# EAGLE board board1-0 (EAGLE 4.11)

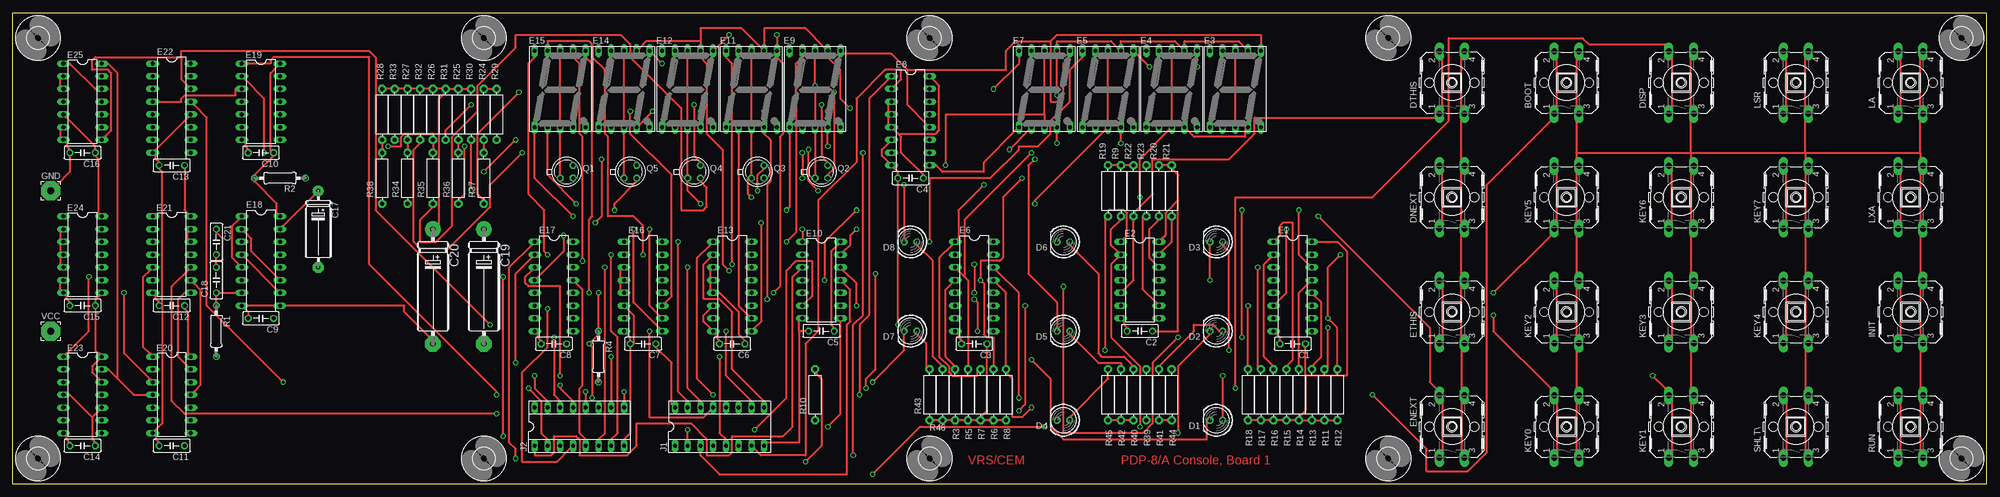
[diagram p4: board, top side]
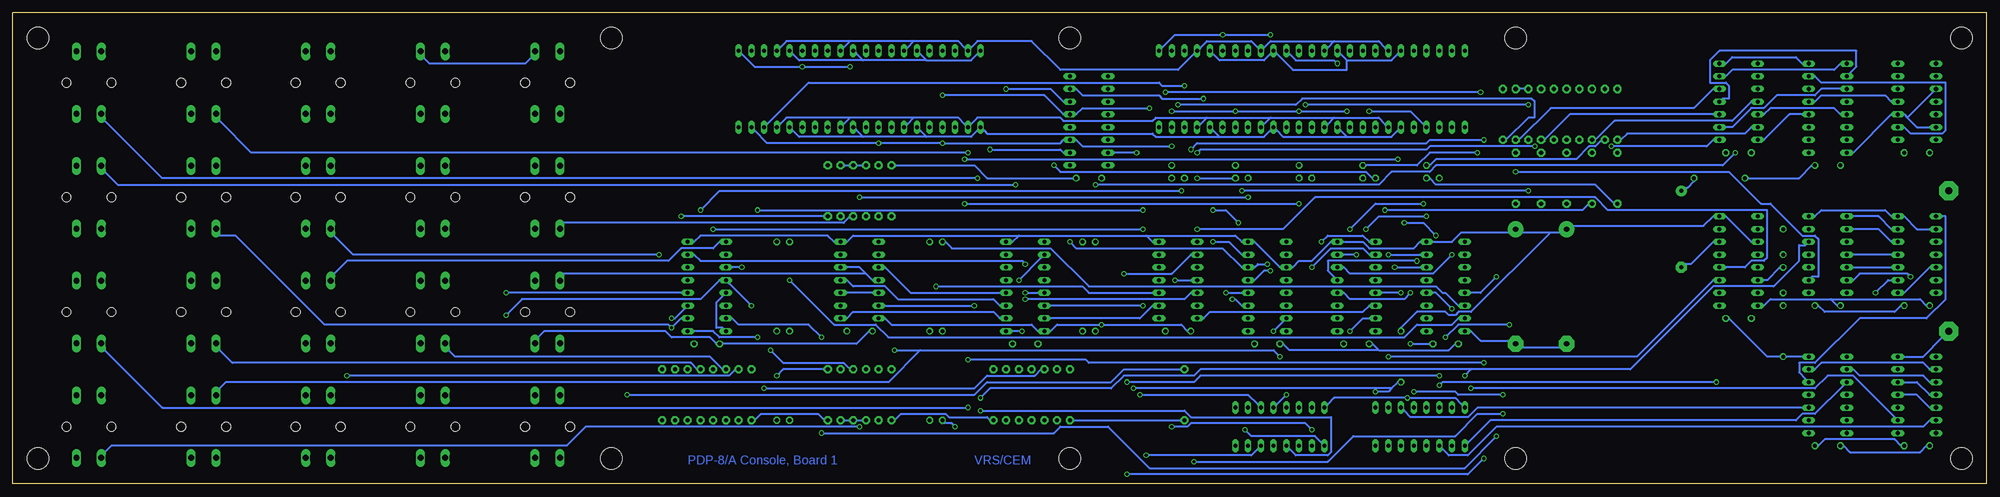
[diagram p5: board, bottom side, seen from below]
Size 393.7 x 93.98 mm. Coordinates in mm from the lower left corner, seen from the top.
Outline: 0,0 0,93.98 393.7,93.98 393.7,0 0,0
Copper layers (1*16): Top 0.035mm / dielectric 1.5mm / Bottom 0.035mm
Design rules "15mils": minimum track width 15mil, minimum drill 24mil, track to track 15mil, track to pad 10mil, pad to pad 10mil, via to via 10mil, smd to smd 10mil, copper to edge 25mil, drill to drill 10mil, minimum pad ring 10mil, minimum via ring 8mil, stop-mask expansion 0mil, vias tented up to drill 0mil, thermal gap 10mil
Net classes: 1 Supply: width 0.381 mm

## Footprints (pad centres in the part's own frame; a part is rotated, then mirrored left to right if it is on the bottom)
B3F-40XX = drill 1.194 long: 1 -6.248,2.489; 2 6.248,2.489; 3 -6.248,-2.489; 4 6.248,-2.489 | hole 1.803: 0,-4.496; 0,4.496
C050-025X075 = drill 0.813 octagon: 1 -2.54,0; 2 2.54,0
E15-5 = drill 0.813 pad 2.159 round: + -7.62,0 | drill 0.813 pad 2.159 octagon: - 7.62,0
E22-6 = drill 1.016 pad 3.15 round: + -11.43,0 | drill 1.016 pad 3.15 octagon: - 11.43,0
LED5MM = drill 0.813 octagon: A -1.27,0; K 1.27,0
DIL16 = drill 0.813 long: 1 -8.89,-3.81; 2 -6.35,-3.81; 3 -3.81,-3.81; 4 -1.27,-3.81; 5 1.27,-3.81; 6 3.81,-3.81; 7 6.35,-3.81; 8 8.89,-3.81; 9 8.89,3.81; 10 6.35,3.81; 11 3.81,3.81; 12 1.27,3.81; 13 -1.27,3.81; 14 -3.81,3.81; 15 -6.35,3.81; 16 -8.89,3.81
DIL14 = drill 0.813 long: 1 -7.62,-3.81; 2 -5.08,-3.81; 3 -2.54,-3.81; 4 0,-3.81; 5 2.54,-3.81; 6 5.08,-3.81; 7 7.62,-3.81; 8 7.62,3.81; 9 5.08,3.81; 10 2.54,3.81; 11 0,3.81; 12 -2.54,3.81; 13 -5.08,3.81; 14 -7.62,3.81
HDSP-M = drill 0.813 long: 1 -5.08,-7.62; 2 -2.54,-7.62; 3 0,-7.62; 4 2.54,-7.62; 5 5.08,-7.62; 6 5.08,7.62; 7 2.54,7.62; 8 0,7.62; 9 -2.54,7.62; 10 -5.08,7.62
3,81/1,4 = drill 1.397 pad 3.81 octagon: 1 0,0
SOCKED-16 = drill 0.813 long: 1 -8.89,-3.81; 2 -6.35,-3.81; 3 -3.81,-3.81; 4 -1.27,-3.81; 5 1.27,-3.81; 6 3.81,-3.81; 7 6.35,-3.81; 8 8.89,-3.81; 9 8.89,3.81; 10 6.35,3.81; 11 3.81,3.81; 12 1.27,3.81; 13 -1.27,3.81; 14 -3.81,3.81; 15 -6.35,3.81; 16 -8.89,3.81
TO18 = drill 0.813 octagon: 1 -1.27,-1.27; 2 1.27,-1.27; 3 1.27,1.27
0207/10 = drill 0.813 octagon: 1 -5.08,0; 2 5.08,0
R-10 = drill 0.813 pad 1.6 octagon: 1 -5.08,0; 2 5.08,0
4,3 = hole 4.3: 0,0

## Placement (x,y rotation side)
BOOT  [B3F-40XX]  309.88,80.01 90 top
C1  0.01  [C050-025X075]  255.27,27.94 180 top
C2  0.01  [C050-025X075]  224.79,30.48 180 top
C3  0.01  [C050-025X075]  191.77,27.94 180 top
C4  0.01  [C050-025X075]  179.07,60.96 180 top
C5  0.01  [C050-025X075]  161.29,30.48 180 top
C6  0.01  [C050-025X075]  143.51,27.94 180 top
C7  0.01  [C050-025X075]  125.73,27.94 180 top
C8  0.01  [C050-025X075]  107.95,27.94 180 top
C9  0.01  [C050-025X075]  49.53,33.02 180 top
C10  0.01  [C050-025X075]  49.53,66.04 180 top
C11  0.01  [C050-025X075]  31.75,7.62 180 top
C12  0.01  [C050-025X075]  31.75,35.56 180 top
C13  0.01  [C050-025X075]  31.75,63.5 180 top
C14  0.01  [C050-025X075]  13.97,7.62 180 top
C15  0.01  [C050-025X075]  13.97,35.56 180 top
C16  0.01  [C050-025X075]  13.97,66.04 180 top
C17  1.0uf  [E15-5]  60.96,50.8 270 top
C18  47pf  [C050-025X075]  40.64,40.64 90 top
C19  6.8uf  [E22-6]  93.98,39.37 270 top
C20  6.8uf  [E22-6]  83.82,39.37 270 top
C21  33pf  [C050-025X075]  40.64,48.26 270 top
D1  MQ  [LED5MM]  240.03,12.7 180 top
D2  SR  [LED5MM]  240.03,30.48 180 top
D3  MD  [LED5MM]  240.03,48.26 180 top
D4  AC  [LED5MM]  209.55,12.7 180 top
D5  STATUS  [LED5MM]  209.55,30.48 180 top
D6  STATE  [LED5MM]  209.55,48.26 180 top
D7  BUS  [LED5MM]  179.07,30.48 180 top
D8  RUN  [LED5MM]  179.07,48.26 180 top
DISP  [B3F-40XX]  332.74,80.01 90 top
DNEXT  [B3F-40XX]  287.02,57.15 90 top
DTHIS  [B3F-40XX]  287.02,80.01 90 top
E1  74LS148N  [DIL16]  255.27,39.37 270 top
E2  74LS08N  [DIL14]  224.79,40.64 270 top
E3  HD-H101  [HDSP-M]  243.84,78.74 0 top
E4  HD-H101  [HDSP-M]  231.14,78.74 0 top
E5  HD-H101  [HDSP-M]  218.44,78.74 0 top
E6  74LS148N  [DIL16]  191.77,39.37 270 top
E7  HD-H101  [HDSP-M]  205.74,78.74 0 top
E8  7446N  [DIL16]  179.07,72.39 270 top
E9  HD-H101  [HDSP-M]  160.02,78.74 0 top
E10  74LS08N  [DIL14]  161.29,40.64 270 top
E11  HD-H101  [HDSP-M]  147.32,78.74 0 top
E12  HD-H101  [HDSP-M]  134.62,78.74 0 top
E13  7446N  [DIL16]  143.51,39.37 270 top
E14  HD-H101  [HDSP-M]  121.92,78.74 0 top
E15  HD-H101  [HDSP-M]  109.22,78.74 0 top
E16  7446N  [DIL16]  125.73,39.37 270 top
E17  74LS145N  [DIL16]  107.95,39.37 270 top
E18  74LS123N  [DIL16]  49.53,44.45 270 top
E19  7416N  [DIL14]  49.53,76.2 270 top
E20  74LS04N  [DIL14]  31.75,17.78 270 top
E21  74LS20N  [DIL14]  31.75,45.72 270 top
E22  74LS42N  [DIL16]  31.75,74.93 270 top
E23  74LS74N  [DIL14]  13.97,17.78 270 top
E24  74LS95N  [DIL14]  13.97,45.72 270 top
E25  74LS90N  [DIL14]  13.97,76.2 270 top
ENEXT  [B3F-40XX]  287.02,11.43 90 top
ETHIS  [B3F-40XX]  287.02,34.29 90 top
GND  [3,81/1,4]  7.62,58.42 0 top
INIT  [B3F-40XX]  378.46,34.29 90 top
J1  [SOCKED-16]  140.97,11.43 0 top
J2  [SOCKED-16]  113.03,11.43 0 top
KEY0  [B3F-40XX]  309.88,11.43 90 top
KEY1  [B3F-40XX]  332.74,11.43 90 top
KEY2  [B3F-40XX]  309.88,34.29 90 top
KEY3  [B3F-40XX]  332.74,34.29 90 top
KEY4  [B3F-40XX]  355.6,34.29 90 top
KEY5  [B3F-40XX]  309.88,57.15 90 top
KEY6  [B3F-40XX]  332.74,57.15 90 top
KEY7  [B3F-40XX]  355.6,57.15 90 top
LA  [B3F-40XX]  378.46,80.01 90 top
LSR  [B3F-40XX]  355.6,80.01 90 top
LXA  [B3F-40XX]  378.46,57.15 90 top
Q1  MPSA05  [TO18]  110.49,62.23 0 top
Q2  MPSA05  [TO18]  161.29,62.23 0 top
Q3  MPSA05  [TO18]  148.59,62.23 0 top
Q4  MPSA05  [TO18]  135.89,62.23 0 top
Q5  MPSA05  [TO18]  123.19,62.23 0 top
R1  10K  [0207/10]  40.64,30.48 270 top
R2  6.8K  [0207/10]  53.34,60.96 0 top
R3  1K  [R-10]  187.96,17.78 90 top
R4  10K  [0207/10]  116.84,25.4 270 top
R5  1K  [R-10]  190.5,17.78 90 top
R6  1K  [R-10]  195.58,17.78 90 top
R7  1K  [R-10]  193.04,17.78 90 top
R8  1K  [R-10]  198.12,17.78 90 top
R9  1K  [R-10]  220.98,58.42 270 top
R10  1K  [R-10]  160.02,17.78 90 top
R11  1K  [R-10]  261.62,17.78 90 top
R12  1K  [R-10]  264.16,17.78 90 top
R13  1K  [R-10]  259.08,17.78 90 top
R14  1K  [R-10]  256.54,17.78 90 top
R15  1K  [R-10]  254,17.78 90 top
R16  1K  [R-10]  251.46,17.78 90 top
R17  1K  [R-10]  248.92,17.78 90 top
R18  1K  [R-10]  246.38,17.78 90 top
R19  1K  [R-10]  218.44,58.42 270 top
R20  1K  [R-10]  228.6,58.42 270 top
R21  1K  [R-10]  231.14,58.42 270 top
R22  1K  [R-10]  223.52,58.42 270 top
R23  1K  [R-10]  226.06,58.42 270 top
R24  470  [R-10]  93.98,73.66 270 top
R25  470  [R-10]  88.9,73.66 270 top
R26  470  [R-10]  83.82,73.66 270 top
R27  470  [R-10]  78.74,73.66 270 top
R28  470  [R-10]  73.66,73.66 270 top
R29  10  [R-10]  96.52,73.66 270 top
R30  10  [R-10]  91.44,73.66 270 top
R31  10  [R-10]  86.36,73.66 270 top
R32  10  [R-10]  81.28,73.66 270 top
R33  27  [R-10]  76.2,73.66 270 top
R34  27  [R-10]  78.74,60.96 90 top
R35  27  [R-10]  83.82,60.96 90 top
R36  27  [R-10]  88.9,60.96 90 top
R37  27  [R-10]  93.98,60.96 90 top
R38  27  [R-10]  73.66,60.96 90 top
R39  330  [R-10]  226.06,17.78 90 top
R40  330  [R-10]  223.52,17.78 90 top
R41  330  [R-10]  228.6,17.78 90 top
R42  330  [R-10]  220.98,17.78 90 top
R43  330  [R-10]  182.88,17.78 90 top
R44  330  [R-10]  231.14,17.78 90 top
R45  330  [R-10]  218.44,17.78 90 top
R46  330  [R-10]  185.42,17.78 90 top
RUN  [B3F-40XX]  378.46,11.43 90 top
SHLT\  [B3F-40XX]  355.6,11.43 90 top
U$2  [4,3]  5.08,5.08 0 top
U$11  [4,3]  93.98,5.08 0 top
U$12  [4,3]  5.08,88.9 0 top
U$13  [4,3]  182.88,5.08 0 top
U$14  [4,3]  274.32,5.08 0 top
U$15  [4,3]  388.62,5.08 0 top
U$16  [4,3]  388.62,88.9 0 top
U$17  [4,3]  274.32,88.9 0 top
U$18  [4,3]  182.88,88.9 0 top
U$19  [4,3]  93.98,88.9 0 top
VCC  [3,81/1,4]  7.62,30.48 0 top

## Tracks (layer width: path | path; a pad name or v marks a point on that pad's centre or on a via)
A  (via drill 0.61)
  Top 0.381: v208.28,77.47 208.28,85.09 E7.7 208.28,87.63 208.28,88.27 219.07,88.27 220.34,87 E5.7 220.98,87.63 220.98,88.27 231.78,88.27 233.04,87 E4.7 233.68,87.63 233.68,88.27 244.47,88.27 245.75,87 E3.7 | v142.88,42.55 141.6,43.81 141.6,66.67 138.43,69.85 138.43,83.82 137.16,85.09 E12.7 137.16,87.63 137.16,88.27 | 137.16,88.27 126.36,88.27 125.09,87 E14.7 | 137.16,88.27 137.16,90.81 145.41,90.81 149.22,87 E11.7 149.86,87.63 149.86,90.81 158.12,90.81 161.93,87 E9.7 162.56,85.09 165.1,82.55 165.1,76.83 v167,74.93
  Bottom 0.381: v208.28,77.47 187.96,77.47 184.15,73.66 E8.13 181.61,73.66 180.34,74.93 v167,74.93 | v142.88,42.55 144.15,42.55 146.05,40.64 E13.13
ADDR0  (via drill 0.61)
  Top 0.381: v142.24,30.48 142.24,21.59 147.32,16.51 J1.10
  Bottom 0.381: v142.24,30.48 140.34,32.38 E13.7
ADDR1  (via drill 0.61)
  Top 0.381: v139.7,17.78 136.53,20.95 136.53,45.09 139.06,47.62 E13.1
  Bottom 0.381: v139.7,17.78 141.6,15.88 J1.12
ADDR2
  Top 0.381: J1.9 149.86,16.51 143.51,22.86 143.51,34.29 140.97,36.83 137.79,36.83 137.79,43.81 139.06,45.09 E13.2
B  (via drill 0.61)
  Top 0.381: v151.76,38.1 153.03,39.37 153.03,69.22 153.67,69.85 153.67,83.82 152.4,85.09 E11.6 152.4,87.63 v152.4,89.53 | v129.54,83.82 127.64,85.72 E14.6 | v142.88,89.53 140.34,87 E12.6 | 178.44,82.55 178.44,75.56 182.25,71.75 E8.12 | 178.44,82.55 175.26,85.72 165.74,85.72 E9.6 | 207.01,88.27 207.01,76.2 208.91,76.2 209.55,76.83 209.55,83.82 210.82,85.09 E7.6 | 207.01,88.27 208.28,89.53 248.92,89.53 248.92,87.63 E3.6 | v226.69,83.19 224.16,85.72 E5.6 | v236.22,83.19 236.22,85.09 E4.6 | 178.44,82.55 198.12,82.55 198.12,86.36 200.03,88.27 207.01,88.27
  Bottom 0.381: v151.76,38.1 148.59,38.1 E13.12 | v129.54,83.82 130.18,84.45 137.79,84.45 139.06,85.72 E12.6 | v142.88,89.53 v152.4,89.53 161.93,89.53 164.47,87 E9.6 | v226.69,83.19 v236.22,83.19 245.75,83.19 248.28,85.72 E3.6
BEMA0  (via drill 0.61)
  Top 0.381: v127,30.48 127,13.34 137.79,13.34 139.06,14.61 J1.13
  Bottom 0.381: v127,30.48 124.46,33.02 123.19,33.02 E16.7
BEMA1  (via drill 0.61)
  Top 0.381: v132.72,48.26 132.72,18.41 134.62,16.51 J1.15
  Bottom 0.381: v132.72,48.26 131.44,49.53 124.46,49.53 123.19,48.26 E16.1
BEMA2  (via drill 0.61)
  Top 0.381: v134.62,43.18 134.62,19.05 137.16,16.51 J1.14
  Bottom 0.381: v134.62,43.18 130.81,46.99 124.46,46.99 123.19,45.72 E16.2
BOOT  (via drill 0.61)
  Top 0.381: BOOT.2 307.98,85.09 307.98,74.93 BOOT.1 306.7,72.39 294,59.69 294,6.35 290.19,2.54 281.94,2.54 281.94,6.99 v271.14,17.78 | v96.52,13.97 34.29,13.97 31.75,16.51 31.75,39.37 34.92,42.55 E21.10 | v158.12,4.45 161.29,7.62 161.29,20.95 160.02,22.23 R10.2
  Bottom 0.381: v271.14,17.78 201.93,17.78 199.39,20.32 174.62,20.32 172.09,22.86 160.66,22.86 R10.2 | v96.52,13.97 101.6,13.97 106.05,9.53 126.36,9.53 131.44,4.45 v158.12,4.45
BPWR-OK  (via drill 0.61)
  Top 0.381: E18.11 52.7,41.27 47.62,46.35 47.62,48.9 46.35,50.16 E18.2 | v119.38,25.4 119.38,16.51 J2.10
  Bottom 0.381: v119.38,25.4 69.85,25.4 54.61,40.64 E18.11
BRUN  (via drill 0.61)
  Top 0.381: v96.52,17.78 96.52,18.41 71.12,43.81 71.12,85.09 52.07,85.09 51.44,84.45 51.44,83.82 46.99,83.82 E19.1 | v114.3,18.41 114.3,16.51 J2.12
  Bottom 0.381: v96.52,17.78 105.41,17.78 106.05,18.41 v114.3,18.41
C  (via drill 0.61)
  Top 0.381: v208.28,67.94 208.28,69.85 E7.4 | v220.98,67.94 220.98,69.85 E5.4 | E4.4 234.31,70.48 235.59,69.22 245.75,69.22 245.75,70.48 E3.4 | v150.5,36.83 150.5,59.69 151.13,60.33 151.13,68.58 149.86,69.85 E11.4 149.86,72.39 v149.86,74.3 | v127.64,74.3 125.09,71.75 E14.4 | v137.16,74.3 137.16,72.39 E12.4 | v162.56,74.3 162.56,72.39 E9.4 162.56,69.85 v162.56,67.31
  Bottom 0.381: E3.4 245.75,70.48 243.21,67.94 v220.98,67.94 v208.28,67.94 184.78,67.94 184.15,68.58 E8.11 181.61,68.58 180.34,67.31 v162.56,67.31 | v150.5,36.83 149.86,36.83 148.59,35.56 E13.11 | v127.64,74.3 v137.16,74.3 v149.86,74.3 v162.56,74.3
D  (via drill 0.61)
  Top 0.381: v198.75,66.67 202.56,70.48 E7.2 | E13.10 146.69,33.66 144.78,35.56 144.78,69.85 E11.2
  Bottom 0.381: v198.75,66.67 184.78,66.67 184.15,66.04 E8.10 | 214,73.03 215.26,71.75 E5.2 | 214,73.03 205.1,73.03 203.84,71.75 E7.2 202.56,71.75 201.29,73.03 184.78,73.03 184.15,72.39 166.37,72.39 165.74,73.03 155.57,73.03 | 226.69,73.03 227.97,71.75 E4.2 | 214,73.03 226.69,73.03 | 226.69,73.03 239.4,73.03 240.66,71.75 E3.2 | 130.18,73.03 121.28,73.03 120.02,71.75 E14.2 | 130.18,73.03 131.44,71.75 E12.2 | 142.88,73.03 144.15,71.75 E11.2 | 142.88,73.03 130.18,73.03 | 155.57,73.03 156.84,71.75 E9.2 | 155.57,73.03 142.88,73.03
DISP  (via drill 0.61)
  Top 0.381: DISP.1 330.83,74.93 330.83,85.09 DISP.2 329.56,87.63 314.32,87.63 313.06,88.9 286.38,88.9 286.38,72.39 271.14,57.15 243.84,57.15 v243.84,19.05 | E6.4 187.32,40.01 186.06,38.73 186.06,25.4 187.96,23.5 R3.2
  Bottom 0.381: v243.84,19.05 201.93,19.05 199.39,21.59 189.87,21.59 188.59,22.86 R3.2
DISP0
  Top 0.381: E17.13 112.39,40.01 113.67,38.73 113.67,19.68 113.03,19.05 113.03,10.16 114.3,8.89 J2.5
DISP1  (via drill 0.61)
  Top 0.381: v118.11,43.18 118.11,10.16 116.84,8.89 J2.6
  Bottom 0.381: v118.11,43.18 113.03,43.18 E17.14
DISP2  (via drill 0.61)
  Top 0.381: v119.38,45.72 119.38,30.48 120.65,29.21 120.65,10.16 119.38,8.89 J2.7
  Bottom 0.381: v119.38,45.72 113.03,45.72 E17.15
DISPINH  (via drill 0.61)
  Top 0.381: v106.68,34.92 106.68,27.3 101.6,22.23 101.6,4.45 108.58,4.45 111.12,6.99 J2.4
  Bottom 0.381: v106.68,34.92 109.86,38.1 110.49,38.1 E17.12
DISPLAY0  (via drill 0.61)
  Top 0.381: v167.64,5.71 167.64,31.75 169.54,33.66 v169.54,66.04
  Bottom 0.381: v167.64,5.71 146.69,5.71 145.41,6.99 J1.6 | v169.54,66.04 173.99,66.04 E8.7
DISPLAY1  (via drill 0.61)
  Top 0.381: v168.91,17.78 168.91,31.75 170.81,33.66 170.81,76.83 174.62,80.64 E8.1
  Bottom 0.381: v168.91,17.78 147.32,17.78 145.41,15.88 J1.11
DISPLAY2
  Top 0.381: J1.7 147.96,6.99 149.22,5.71 158.12,5.71 158.12,27.94 160.66,30.48 160.66,56.52 168.28,64.14 168.28,76.83 173.99,82.55 177.16,82.55 177.16,80.64 175.9,79.38 E8.2
DNEXT
  Top 0.381: DNEXT.1 285.12,52.07 285.12,62.23 DNEXT.2 | E2.9 227.97,36.2 225.43,38.73 225.43,53.34 R23.2
  Bottom 0.381: DNEXT.1 283.85,52.07 227.97,52.07 226.69,53.34 R23.2
DTHIS
  Top 0.381: DTHIS.2 285.12,85.09 285.12,74.93 DTHIS.1 283.85,73.03 247.65,73.03 247.65,69.85 242.57,64.77 227.33,64.77 227.33,57.78 223.52,53.98 R22.2 223.52,52.7 223.52,40.64 221.62,38.73 E2.5
  Bottom 0.381: E2.5 222.25,38.1 227.33,38.1 E2.10
E  (via drill 0.61)
  Top 0.381: E8.9 184.15,63.5 185.42,62.23 193.68,62.23 193.68,64.14 200.03,70.48 E7.1 | v149.22,52.07 149.22,32.38 147.96,31.11 E13.9 | v154.31,54.61 154.94,55.24 154.94,69.85 E9.1
  Bottom 0.381: 211.46,69.22 212.72,70.48 E5.1 | 211.46,69.22 202.56,69.22 201.29,70.48 E7.1 200.03,70.48 199.39,69.85 166.37,69.85 165.74,69.22 153.03,69.22 | 224.16,69.22 225.43,70.48 E4.1 | 211.46,69.22 224.16,69.22 | 224.16,69.22 236.85,69.22 238.12,70.48 E3.1 | 127.64,69.22 118.75,69.22 117.47,70.48 E14.1 | 127.64,69.22 128.91,70.48 E12.1 | 127.64,69.22 140.34,69.22 141.6,70.48 E11.1 142.88,70.48 144.15,69.22 153.03,69.22 | v149.22,52.07 151.76,54.61 v154.31,54.61 | 153.03,69.22 154.31,70.48 E9.1
ENEXT  (via drill 0.61)
  Top 0.381: E2.13 229.24,46.35 231.14,48.26 231.14,52.7 R21.2 | ENEXT.1 285.12,6.35 285.12,16.51 ENEXT.2 283.85,19.05 282.57,20.32 282.57,31.11 v260.35,53.34
  Bottom 0.381: v260.35,53.34 231.78,53.34 R21.2
ETHIS
  Top 0.381: ETHIS.1 285.12,29.21 285.12,39.37 ETHIS.2 | E2.12 227.97,43.81 226.69,45.09 226.69,50.8 228.6,52.7 R20.2
  Bottom 0.381: 223.52,41.91 224.79,43.18 227.33,43.18 E2.12 | 223.52,41.91 222.25,40.64 E2.4 | 223.52,41.91 283.85,41.91 ETHIS.2
EXTPUL\  (via drill 0.61)
  Top 0.381: v121.92,18.41 121.92,16.51 J2.9 | v172.09,41.91 172.09,22.86 170.18,20.95 v170.18,19.05
  Bottom 0.381: 118.75,19.05 119.38,18.41 v121.92,18.41 | 118.75,19.05 117.47,20.32 R4.2 | v172.09,41.91 162.56,41.91 158.75,45.72 E10.2 | 118.75,19.05 v170.18,19.05
F  (via drill 0.61)
  Top 0.381: v154.31,48.26 156.21,50.16 v156.21,76.83 156.21,83.82 157.48,85.09 E9.9
  Bottom 0.381: 214,88.27 215.26,87 E5.9 | 214,88.27 205.1,88.27 203.84,87 E7.9 202.56,87 201.29,88.27 190.5,88.27 184.78,82.55 161.29,82.55 158.12,85.72 E9.9 156.84,87 155.57,88.27 146.69,88.27 145.41,87 E11.9 144.15,87 142.88,88.27 130.18,88.27 | 226.69,88.27 227.97,87 E4.9 | 214,88.27 226.69,88.27 | 226.69,88.27 239.4,88.27 240.66,87 E3.9 | 130.18,88.27 121.28,88.27 120.02,87 E14.9 | 130.18,88.27 131.44,87 E12.9 | v154.31,48.26 151.13,48.26 148.59,45.72 E13.15 | v156.21,76.83 164.47,76.83 165.1,77.47 180.34,77.47 181.61,78.74 E8.15
FUN\  (via drill 0.61)
  Top 0.381: E21.13 34.92,50.16 34.92,48.9 E21.12 | v104.14,21.59 104.14,19.05 106.68,16.51 J2.15 | v200.66,17.14 200.66,38.1 196.22,42.55 E6.14
  Bottom 0.381: 102.87,22.86 v104.14,21.59 | 102.87,22.86 71.12,22.86 54.61,39.37 42.55,39.37 37.47,44.45 37.47,47.62 36.2,47.62 E21.12 | v200.66,17.14 198.75,19.05 174.62,19.05 172.09,21.59 158.12,21.59 156.84,22.86 102.87,22.86
G  (via drill 0.61)
  Top 0.381: v195.58,78.74 200.66,83.82 200.66,85.09 E7.10 | v143.51,43.81 143.51,83.82 142.24,85.09 E11.10 | v182.88,48.26 182.88,60.96 194.94,60.96 200.66,66.67 200.66,67.31 204.47,67.31 207.01,69.85 207.01,72.39 210.82,76.2 210.82,82.55 213.36,85.09 E5.10
  Bottom 0.381: v195.58,78.74 186.69,78.74 184.15,76.2 E8.14 | 211.46,84.45 212.72,85.72 E5.10 | 211.46,84.45 202.56,84.45 201.29,85.72 E7.10 | 224.16,84.45 225.43,85.72 E4.10 | 211.46,84.45 224.16,84.45 | 224.16,84.45 236.85,84.45 238.12,85.72 E3.10 | 127.64,84.45 118.75,84.45 117.47,85.72 E14.10 | 127.64,84.45 128.91,85.72 E12.10 | E9.10 154.31,85.72 153.03,84.45 144.15,84.45 142.88,85.72 E11.10 141.6,85.72 138.43,82.55 127.64,82.55 127.64,84.45 | v143.51,43.81 145.41,43.81 146.05,43.18 E13.14 148.59,43.18 152.4,46.99 181.61,46.99 v182.88,48.26
GND  (via drill 0.61)
  Top 0.381: 380.37,66.04 380.37,72.39 LA.3 380.37,74.93 380.37,85.09 LA.4 | 380.37,66.04 380.37,64.77 LXA.4 380.37,62.23 380.37,52.07 LXA.3 380.37,49.53 380.37,41.91 INIT.4 380.37,39.37 380.37,29.21 INIT.3 380.37,26.67 380.37,19.05 RUN.4 380.37,16.51 380.37,6.35 RUN.3 | 357.5,66.04 357.5,72.39 LSR.3 357.5,74.93 357.5,85.09 LSR.4 | 357.5,66.04 357.5,64.77 KEY7.4 357.5,62.23 357.5,52.07 KEY7.3 357.5,49.53 357.5,41.91 KEY4.4 357.5,39.37 357.5,29.21 KEY4.3 357.5,26.67 357.5,19.05 SHLT\.4 357.5,16.51 357.5,6.35 SHLT\.3 | 334.64,66.04 334.64,72.39 DISP.3 334.64,74.93 334.64,85.09 DISP.4 | 334.64,66.04 334.64,64.77 KEY6.4 334.64,62.23 334.64,52.07 KEY6.3 334.64,49.53 334.64,41.91 KEY3.4 334.64,39.37 334.64,29.21 KEY3.3 334.64,26.67 334.64,19.05 KEY1.4 334.64,16.51 334.64,6.35 KEY1.3 | DTHIS.4 288.93,85.09 288.93,74.93 DTHIS.3 288.93,72.39 288.93,64.77 DNEXT.4 288.93,62.23 288.93,52.07 DNEXT.3 288.93,49.53 288.93,41.91 ETHIS.4 288.93,39.37 288.93,29.21 ETHIS.3 288.93,26.67 288.93,19.05 ENEXT.4 288.93,16.51 288.93,6.35 ENEXT.3 | 311.79,66.04 311.79,72.39 BOOT.3 311.79,74.93 311.79,85.09 BOOT.4 | 311.79,66.04 311.79,64.77 KEY5.4 311.79,62.23 311.79,52.07 KEY5.3 311.79,49.53 311.79,41.91 KEY2.4 311.79,39.37 311.79,29.21 KEY2.3 311.79,26.67 311.79,19.05 KEY0.4 311.79,16.51 311.79,6.35 KEY0.3 | 311.79,66.04 334.64,66.04 | 334.64,66.04 357.5,66.04 | 357.5,66.04 380.37,66.04 | E25.3 9.53,79.38 9.53,80.64 E25.2 | E25.6 9.53,70.48 9.53,69.22 E25.7 10.79,67.94 10.79,67.31 11.43,66.67 C16.2 11.43,65.41 11.43,62.23 8.89,59.69 GND.1 | C10.2 46.99,66.67 46.35,67.31 46.35,67.94 E19.7
  Top 0.381: E22.12 34.92,73.03 28.57,66.67 E22.8 28.57,65.41 28.57,64.77 29.21,64.14 C13.2 29.21,62.87 29.84,62.23 29.84,35.56 | C14.2 11.43,8.26 10.79,8.89 10.79,9.53 E23.7 | C11.2 29.21,8.26 28.57,8.89 28.57,9.53 E20.7 28.57,10.79 29.84,12.06 29.84,35.56 | C15.2 11.43,36.2 10.79,36.83 10.79,37.47 E24.7 9.53,38.73 9.53,40.01 E24.6 | C12.2 29.21,36.2 28.57,36.83 28.57,37.47 E21.7 | C9.2 46.99,33.66 46.99,34.29 46.35,34.92 E18.8 46.99,35.56 52.07,35.56 E18.9 54.61,35.56 78.11,35.56 78.11,34.29 83.19,29.21 C20.- | C12.2 29.84,35.56 | C12.2 29.84,35.56 | C2.2 222.25,31.11 221.62,31.75 221.62,32.38 E2.7 | E1.8 252.09,29.84 252.73,29.21 252.73,28.57 C1.2 | C8.2 105.41,28.57 104.78,29.21 104.78,29.84 E17.8 | J2.8 121.92,8.89 123.19,10.16 123.19,27.3 C7.2 | E16.8 122.56,29.84 123.19,29.21 123.19,28.57 C7.2 | E16.6 122.56,34.92 123.83,33.66 123.83,27.94 C7.2 | E8.6 174.62,67.94 173.35,66.67 173.35,65.41 174.62,64.14 E8.8 175.9,62.87 176.53,62.23 176.53,61.59 C4.2 176.53,60.33 v176.53,31.75 | C6.2 140.97,28.57 140.34,29.21 140.34,29.84 E13.8 139.06,31.11 137.79,32.38 137.79,33.66 139.06,34.92 E13.6 | C3.2 189.23,28.57 188.59,29.21 188.59,29.84 E6.8 | 156.84,30.48 156.84,32.38 E10.7 | 156.84,30.48 156.84,8.26 150.5,8.26 J1.8 | 156.84,30.48 158.12,30.48 C5.2
  Bottom 0.381: DTHIS.4 290.19,85.09 291.46,83.82 310.51,83.82 311.79,85.09 BOOT.4 | 15.88,73.03 13.97,71.12 11.43,71.12 E25.6 | 15.88,73.03 16.51,73.66 E25.10 19.05,73.66 26.67,66.04 E22.8 | 15.88,73.03 10.79,78.11 E25.3 | E19.7 44.45,68.58 39.37,73.66 36.83,73.66 E22.12 | C14.2 12.06,7.62 13.34,6.35 27.3,6.35 28.57,7.62 C11.2 | 31.11,36.83 29.84,35.56 C12.2 | 31.11,36.83 43.18,36.83 44.45,35.56 E18.8 | 31.11,36.83 13.34,36.83 12.06,35.56 C15.2 | E1.5 252.09,37.47 253.37,36.2 253.37,31.11 252.09,31.11 E1.8 | C2.2 222.88,30.48 225.43,27.94 252.09,27.94 C1.2 253.37,27.94 254.63,29.21 262.25,29.21 263.52,30.48 287.65,30.48 288.93,29.21 ETHIS.3 | E17.8 102.87,30.48 100.97,28.57 95.25,28.57 C19.- 92.71,27.3 85.09,27.3 C20.- | 121.28,26.67 107.31,26.67 106.05,27.94 C8.2 | 121.28,26.67 122.56,27.94 C7.2 | 121.28,26.67 139.06,26.67 140.34,27.94 C6.2 | C5.2 159.38,30.48 160.66,31.75 v176.53,31.75 185.42,31.75 186.69,30.48 E6.8 189.23,30.48 190.5,31.75 218.44,31.75 219.71,33.02 E2.7 | E16.6 123.19,35.56 124.46,34.29 154.94,34.29 156.21,33.02 E10.7
INIT  (via drill 0.61)
  Top 0.381: INIT.1 376.56,29.21 376.56,39.37 INIT.2 | E6.13 196.22,40.01 198.12,38.1 198.12,23.5 R8.2 198.12,22.23 199.39,20.95 199.39,13.34 201.29,13.34 v203.2,15.24
  Bottom 0.381: v203.2,15.24 363.86,15.24 375.29,26.67 INIT.1
KEY0  (via drill 0.61)
  Top 0.381: KEY0.1 307.98,6.35 307.98,16.51 KEY0.2 306.7,19.05 295.27,30.48 v295.27,33.66 | v246.38,35.56 246.38,23.5 R18.2
  Bottom 0.381: v246.38,35.56 250.82,40.01 E1.4 252.73,40.64 256.54,36.83 292.1,36.83 v295.27,33.66
KEY1  (via drill 0.61)
  Top 0.381: KEY1.1 330.83,6.35 330.83,16.51 KEY1.2 329.56,19.05 v327.02,21.59 | v248.28,43.18 248.28,22.86 R17.2
  Bottom 0.381: v248.28,43.18 250.19,43.18 E1.3 | v327.02,21.59 250.82,21.59 249.56,22.86 R17.2
KEY2
  Top 0.381: KEY2.1 307.98,29.21 307.98,39.37 KEY2.2 | E1.2 250.82,45.09 249.56,43.81 249.56,25.4 251.46,23.5 R16.2
  Bottom 0.381: KEY2.1 306.7,26.67 305.44,25.4 254.63,25.4 252.09,22.86 R16.2
KEY3
  Top 0.381: KEY3.1 330.83,29.21 330.83,39.37 KEY3.2 | E1.1 252.09,48.9 252.73,49.53 252.73,51.44 253.37,52.07 255.27,52.07 255.27,24.77 254,23.5 R15.2
  Bottom 0.381: KEY3.2 329.56,41.91 327.02,44.45 262.89,44.45 260.35,46.99 254,46.99 252.73,48.26 E1.1
KEY4
  Top 0.381: KEY4.1 353.69,29.21 353.69,39.37 KEY4.2 | E1.13 258.44,40.01 256.54,38.1 256.54,23.5 R14.2
  Bottom 0.381: KEY4.1 352.43,26.67 349.88,24.13 258.44,24.13 257.18,22.86 R14.2
KEY5  (via drill 0.61)
  Top 0.381: KEY5.2 307.98,62.23 307.98,52.07 KEY5.1 306.7,49.53 v295.27,38.1 | E1.12 259.71,37.47 260.99,36.2 260.99,25.4 259.08,23.5 R13.2
  Bottom 0.381: v295.27,38.1 260.35,38.1 E1.12
KEY6  (via drill 0.61)
  Top 0.381: KEY6.1 330.83,52.07 330.83,62.23 KEY6.2 | R12.2 264.16,23.5 264.16,31.11 v262.25,33.02 262.25,43.18 v264.8,45.72
  Bottom 0.381: v262.25,33.02 261.62,33.02 259.71,34.92 E1.11 | v264.8,45.72 325.75,45.72 329.56,49.53 KEY6.1
KEY7  (via drill 0.61)
  Top 0.381: v262.25,31.11 262.25,22.86 R11.2 | KEY7.1 353.69,52.07 353.69,62.23 KEY7.2
  Bottom 0.381: E1.10 260.35,33.02 v262.25,31.11 262.89,31.75 331.47,31.75 349.25,49.53 352.43,49.53 KEY7.1
KEY-F\
  Bottom 0.381: E23.6 11.43,12.7 12.7,11.43 97.79,11.43 103.5,5.71 107.31,5.71 108.58,6.99 J2.3
KEYSTB  (via drill 0.61)
  Top 0.381: v102.87,19.05 105.41,16.51 105.41,10.16 106.68,8.89 J2.2
  Bottom 0.381: v102.87,19.05 34.29,19.05 31.75,21.59 26.67,21.59 18.41,13.34 E23.9
KFUN0\
  Top 0.381: J1.3 137.16,6.35 137.16,5.71 140.97,1.91 166.37,1.91 166.37,31.75 167,32.38 167,38.73 165.74,40.01 E10.11
KFUN1\  (via drill 0.61)
  Top 0.381: v134.62,10.79 134.62,8.89 J1.2 | v162.56,11.43 165.1,13.97 165.1,32.38 E10.8
  Bottom 0.381: v134.62,10.79 135.89,12.06 158.75,12.06 159.38,11.43 v162.56,11.43
KFUN2\  (via drill 0.61)
  Top 0.381: v147.96,10.79 154.31,17.14 154.31,42.55 156.21,44.45 159.38,44.45 159.38,37.47 158.12,36.2 E10.6
  Bottom 0.381: v147.96,10.79 146.69,9.53 133.99,9.53 132.72,8.26 J1.1
LA  (via drill 0.61)
  Top 0.381: LA.1 376.56,74.93 376.56,85.09 LA.2 | v201.29,60.96 197.49,57.15 197.49,45.09 196.85,44.45 193.04,44.45 v193.04,40.64 193.68,40.01 193.68,29.84 194.31,29.21 195.58,29.21 195.58,23.5 R6.2
  Bottom 0.381: v193.04,40.64 188.59,45.09 E6.2 | v201.29,60.96 363.86,60.96 375.29,72.39 LA.1
LSR  (via drill 0.61)
  Top 0.381: LSR.1 353.69,74.93 353.69,85.09 LSR.2 | 189.87,41.27 190.5,40.64 190.5,23.5 R5.2 | 189.87,41.27 188.59,42.55 E6.3 | v203.2,66.04 189.87,52.7 189.87,41.27
  Bottom 0.381: v203.2,66.04 346.07,66.04 352.43,72.39 LSR.1
LXA  (via drill 0.61)
  Top 0.381: LXA.1 376.56,52.07 376.56,62.23 LXA.2 | v193.68,59.69 188.59,54.61 188.59,48.9 E6.1 187.32,47.62 184.78,45.09 184.78,25.4 186.69,23.5 186.69,22.23 187.32,21.59 192.41,21.59 192.41,22.86 R7.2
  Bottom 0.381: v193.68,59.69 372.75,59.69 375.29,62.23 LXA.2
MCLOCK
  Top 0.381: 20.95,20.95 24.13,17.78 26.67,17.78 E20.4 | 20.95,20.95 19.05,22.86 E23.13 | 20.95,20.95 20.95,81.92 19.05,83.82 E25.14
MCLOCK\  (via drill 0.61)
  Top 0.381: v22.23,38.1 22.23,26.04 27.3,20.95 E20.3 | E10.3 156.84,42.55 155.57,41.27 155.57,11.43 153.67,9.53 143.51,9.53 143.51,6.35 142.88,5.71 138.43,5.71 138.43,8.89 135.25,12.06 124.46,12.06 124.46,7.62 122.56,5.71 113.03,5.71 113.03,8.89 112.39,9.53 107.95,9.53 107.95,6.35 107.31,5.71 104.14,5.71 104.14,6.35 J2.1
  Bottom 0.381: v22.23,38.1 19.68,40.64 19.05,40.64 E24.9 | J2.1 103.5,8.26 99.06,12.7 38.1,12.7 36.83,13.97 34.29,13.97 28.57,19.68 E20.3
MPXA  (via drill 0.61)
  Top 0.381: 33.66,85.09 16.51,85.09 15.88,84.45 15.88,82.55 19.05,82.55 19.68,81.92 19.68,70.48 18.41,69.22 E25.8 | 33.66,85.09 33.66,80.64 34.92,79.38 E22.14 | v107.95,29.21 107.95,17.78 109.22,16.51 J2.14 | v95.25,31.75 72.39,54.61 72.39,85.09 71.12,86.36 33.66,86.36 33.66,85.09
  Bottom 0.381: v107.95,29.21 105.41,31.75 v95.25,31.75
MPXB  (via drill 0.61)
  Top 0.381: v109.22,19.68 109.22,19.05 111.76,16.51 J2.13 | v53.98,20.32 38.73,35.56 38.73,73.03 36.2,75.56 E22.13
  Bottom 0.381: E25.11 19.05,76.2 20.32,77.47 33.02,77.47 34.29,76.2 E22.13 | v109.22,19.68 108.58,20.32 v53.98,20.32
N$1  (via drill 0.61)
  Top 0.381: v254,50.8 254,38.1 252.09,36.2 E1.6 | v168.28,50.8 167,49.53 167,47.62 165.74,46.35 E10.13
  Bottom 0.381: v254,50.8 v168.28,50.8
N$2  (via drill 0.61)
  Top 0.381: v232.41,29.21 227.33,24.13 227.33,12.06 225.43,10.16 209.55,10.16 v209.55,39.37
  Bottom 0.381: v232.41,29.21 234.95,31.75 248.92,31.75 250.19,33.02 E1.7 | v209.55,39.37 180.34,39.37 179.07,38.1 166.37,38.1 E10.10
N$3  (via drill 0.61)
  Top 0.381: v245.11,29.21 v245.11,54.61 | v168.28,54.61 161.93,48.26 v161.93,40.64
  Bottom 0.381: v245.11,29.21 252.73,29.21 254,30.48 257.81,30.48 E1.9 | v245.11,54.61 v168.28,54.61 | v161.93,40.64 158.75,40.64 E10.4
N$4  (via drill 0.61)
  Top 0.381: E20.11 36.2,18.41 37.47,19.68 37.47,38.73 36.2,40.01 E21.9 | v256.54,54.61 256.54,45.72 258.44,43.81 E1.14 | v160.66,58.42 158.75,60.33 v158.75,66.67 | v100.33,68.58 v93.98,62.23
  Bottom 0.381: v256.54,54.61 252.73,58.42 v160.66,58.42 | v158.75,66.67 157.48,67.94 111.76,67.94 111.12,68.58 v100.33,68.58 | v93.98,62.23 51.44,62.23 45.09,55.88 43.18,55.88 36.83,49.53 34.29,49.53 33.66,48.9 33.66,41.27 34.92,41.27 E21.9
N$5  (via drill 0.61)
  Top 0.381: v168.28,35.56 168.28,40.01 165.74,42.55 E10.12
  Bottom 0.381: v168.28,35.56 186.69,35.56 E6.6
N$6
  Bottom 0.381: E10.9 166.37,35.56 168.91,33.02 186.69,33.02 E6.7
N$7  (via drill 0.61)
  Top 0.381: v191.77,36.83 192.41,36.2 v192.41,30.48
  Bottom 0.381: v191.77,36.83 160.02,36.83 158.75,38.1 E10.5 | v192.41,30.48 194.31,30.48 E6.9
N$8  (via drill 0.61)
  Top 0.381: v191.77,43.81 v191.77,38.1
  Bottom 0.381: v191.77,38.1 189.23,38.1 E6.5 | v191.77,43.81 192.41,44.45 256.54,44.45 257.81,45.72 E1.15
N$9
  Bottom 0.381: E24.13 19.05,50.8 21.59,53.34 26.67,53.34 E21.1
N$10
  Bottom 0.381: E24.12 19.05,48.26 21.59,50.8 26.67,50.8 E21.2
N$11
  Bottom 0.381: E24.11 19.05,45.72 26.67,45.72 E21.4
N$12
  Top 0.381: E20.1 27.3,26.04 26.04,27.3 26.04,41.27 27.3,42.55 E21.5
  Bottom 0.381: E24.10 19.05,43.18 26.67,43.18 E21.5
N$13  (via drill 0.61)
  Top 0.381: v15.24,41.27 15.24,30.48 10.79,26.04 E23.1
  Bottom 0.381: v15.24,41.27 15.88,41.91 25.4,41.91 26.67,40.64 E21.6
N$14
  Bottom 0.381: E23.3 11.43,20.32 12.7,21.59 25.4,21.59 26.67,22.86 E20.2
N$15
  Top 0.381: E21.8 34.29,38.1 33.02,36.83 33.02,25.4 34.92,23.5 E20.13
  Bottom 0.381: E23.2 11.43,22.86 12.7,24.13 33.02,24.13 34.29,22.86 E20.13
N$16
  Bottom 0.381: E20.12 36.2,20.95 37.47,22.23 37.47,24.13 34.29,24.13 25.4,33.02 12.06,33.02 8.26,36.83 8.26,53.34 8.89,53.34 E24.1
N$17
  Bottom 0.381: E23.5 11.43,15.24 13.97,17.78 16.51,17.78 E23.11
N$18
  Top 0.381: E18.5 45.09,43.81 43.81,45.09 43.81,51.44 45.09,52.7 E18.1
N$19
  Top 0.381: R1.1 40.64,36.2 40.64,37.47 C18.1 41.27,38.1 41.91,38.1 | 41.91,38.1 44.45,38.1 E18.7 | 41.91,38.1 41.91,48.9 40.64,50.16 C21.1
N$20
  Top 0.381: E18.15 53.98,51.44 60.33,57.78 C17.+
  Bottom 0.381: R2.2 58.42,60.33 59.69,59.05 60.33,59.05 C17.+
N$21
  Top 0.381: C21.2 40.64,45.09 40.64,43.81 C18.2
  Bottom 0.381: C18.2 41.27,43.18 43.81,40.64 44.45,40.64 E18.6
N$22
  Bottom 0.381: E18.14 54.61,48.26 59.05,43.81 60.33,43.81 C17.-
N$23
  Bottom 0.381: E6.12 196.85,38.1 214.63,38.1 219.71,43.18 E2.3
N$24
  Top 0.381: E18.4 46.35,45.09 52.7,38.73 E18.10
N$25
  Bottom 0.381: E6.11 196.85,35.56 198.12,36.83 217.17,36.83 219.71,39.37 226.06,39.37 227.33,40.64 E2.11
N$26
  Bottom 0.381: E6.10 196.85,33.02 198.12,34.29 226.06,34.29 227.33,33.02 E2.8
N$27  (via drill 0.61)
  Top 0.381: v157.48,50.8 157.48,48.9 E10.1
  Bottom 0.381: v157.48,50.8 140.34,50.8 133.99,57.15 78.11,57.15 75.56,54.61 43.81,54.61 43.81,45.09 44.45,44.45 46.99,44.45 48.26,43.18 52.07,43.18 E18.12
N$28  (via drill 0.61)
  Top 0.381: v113.67,44.45 113.67,69.22 113.03,69.85 113.03,83.82 111.76,85.09 E15.7
  Bottom 0.381: v113.67,44.45 131.44,44.45 131.44,42.55 130.18,41.27 E16.13
N$29  (via drill 0.61)
  Top 0.381: v114.94,38.1 114.94,52.7 115.57,53.34 115.57,83.82 114.3,85.09 E15.6
  Bottom 0.381: v114.94,38.1 116.2,36.83 127,36.83 128.27,38.1 E16.12
N$30  (via drill 0.61)
  Top 0.381: v123.19,74.3 123.19,69.85 131.44,61.59 131.44,37.47 130.18,36.2 E16.11
  Bottom 0.381: v123.19,74.3 114.94,74.3 112.39,71.75 E15.4
N$31  (via drill 0.61)
  Top 0.381: v127,50.8 127,35.56 128.91,33.66 E16.10 | v112.39,55.88 106.68,61.59 106.68,69.85 E15.2
  Bottom 0.381: v127,50.8 121.92,55.88 v112.39,55.88
N$32  (via drill 0.61)
  Top 0.381: v123.83,50.8 123.83,36.2 128.91,31.11 E16.9 | v111.76,53.34 104.14,60.96 104.14,69.85 E15.1
  Bottom 0.381: v123.83,50.8 121.28,53.34 v111.76,53.34
N$33  (via drill 0.61)
  Top 0.381: v125.73,45.72 125.73,51.44 123.83,53.34 118.75,53.34 118.75,69.22 118.11,69.85 118.11,82.55 115.57,85.09 115.57,87.63 114.94,88.27 106.68,88.27 106.68,87.63 E15.9
  Bottom 0.381: v125.73,45.72 128.27,45.72 E16.15
N$34  (via drill 0.61)
  Top 0.381: v106.68,45.72 106.05,46.35 106.05,54.61 102.87,57.78 102.87,83.82 104.14,85.09 E15.10
  Bottom 0.381: v106.68,45.72 110.49,41.91 127,41.91 128.27,43.18 E16.14
N$35
  Top 0.381: R37.2 93.98,66.67 93.98,67.94 R24.2
  Bottom 0.381: E19.12 54.61,78.74 58.42,74.93 87,74.93 93.34,68.58 R24.2
N$36
  Top 0.381: R36.2 88.9,66.67 88.9,67.94 R25.2
  Bottom 0.381: E19.10 54.61,73.66 83.19,73.66 88.27,68.58 R25.2
N$37
  Bottom 0.381: E25.9 16.51,71.12 15.24,69.85 8.89,69.85 8.26,70.48 8.26,80.01 33.02,80.01 34.29,81.28 E22.15
N$38  (via drill 0.61)
  Top 0.381: v242.57,26.67 242.57,46.35 241.3,47.62 D3.A
  Bottom 0.381: v242.57,26.67 240.03,24.13 227.97,24.13 226.69,22.86 R39.2
N$39
  Top 0.381: E25.1 11.43,83.82 16.51,78.74 E25.12
N$40  (via drill 0.61)
  Top 0.381: v74.93,67.31 77.47,67.31 77.47,69.22 78.11,69.85 83.82,69.85 83.82,69.22 R26.2 83.82,67.94 83.82,66.67 R35.2
  Bottom 0.381: v74.93,67.31 55.88,67.31 54.61,68.58 E19.8
N$41
  Bottom 0.381: E22.1 29.21,83.82 30.48,82.55 50.8,82.55 52.07,81.28 E19.13
N$42
  Bottom 0.381: E22.2 27.3,81.92 26.04,83.19 26.04,86.36 53.34,86.36 55.24,84.45 55.24,80.01 52.07,80.01 51.44,79.38 51.44,76.83 52.7,76.83 E19.11
N$43
  Bottom 0.381: E22.3 29.21,78.74 33.02,78.74 34.29,77.47 41.91,77.47 44.45,74.93 46.99,74.93 50.8,71.12 52.07,71.12 E19.9
N$44
  Top 0.381: E22.4 29.21,76.2 33.66,76.2 33.66,76.83 34.29,77.47 44.45,77.47 44.45,78.74 E19.3
N$45
  Bottom 0.381: E22.5 29.21,73.66 30.48,74.93 43.18,74.93 44.45,73.66 E19.5
N$46
  Top 0.381: R34.2 78.74,66.67 78.74,67.94 R27.2
  Bottom 0.381: E19.4 46.99,76.2 50.8,72.39 74.3,72.39 78.11,68.58 R27.2
N$47
  Top 0.381: Q1.1 109.22,61.59 109.22,69.85 E15.3 109.22,72.39 109.22,85.09 E15.8
N$48  (via drill 0.61)
  Top 0.381: v161.29,75.56 161.29,65.41 162.56,64.14 Q2.3
  Bottom 0.381: v161.29,75.56 137.79,75.56 136.53,76.83 90.81,76.83 90.17,76.2 90.17,73.03 91.44,73.03 95.89,68.58 R29.2
N$49  (via drill 0.61)
  Top 0.381: v148.59,58.42 148.59,61.59 149.86,62.87 Q3.3 | v91.44,58.42 91.44,67.94 R30.2
  Bottom 0.381: v91.44,58.42 v148.59,58.42
N$50  (via drill 0.61)
  Top 0.381: v135.89,75.56 135.89,65.41 137.16,64.14 Q4.3 | v91.44,75.56 86.36,70.48 86.36,69.22 R31.2
  Bottom 0.381: v91.44,75.56 v135.89,75.56
N$51  (via drill 0.61)
  Top 0.381: v101.6,66.04 95.25,59.69 95.25,55.24 87,46.99 81.28,46.99 80.01,48.26 80.01,66.67 81.28,67.94 R32.2
  Bottom 0.381: v101.6,66.04 111.12,66.04 113.67,63.5 123.83,63.5 Q5.3
N$52
  Bottom 0.381: Q1.3 111.12,63.5 109.86,64.77 81.92,64.77 79.38,67.31 78.11,67.31 76.83,68.58 R33.2
N$53
  Bottom 0.381: Q1.2 111.12,60.96 109.86,59.69 78.11,59.69 74.3,55.88 R38.1
N$54  (via drill 0.61)
  Top 0.381: 205.74,73.66 205.74,85.09 E7.8 | 205.74,73.66 205.74,72.39 E7.3 | Q5.1 121.92,61.59 121.92,69.85 E14.3 121.92,72.39 121.92,85.09 E14.8 | 205.74,73.66 186.06,73.66 v186.06,63.5
  Bottom 0.381: v186.06,63.5 184.78,62.23 123.83,62.23 122.56,60.96 Q5.1
N$55  (via drill 0.61)
  Top 0.381: v120.02,54.61 120.02,55.88 124.46,60.33 Q5.2
  Bottom 0.381: v120.02,54.61 80.64,54.61 79.38,55.88 R34.1
N$56
  Top 0.381: Q4.2 137.16,60.33 138.43,59.05 138.43,55.24 137.79,54.61 133.35,54.61 133.35,74.93 123.19,85.09 123.19,87.63 121.28,89.53 100.33,89.53 100.33,87 92.71,79.38 92.71,74.3 87.63,69.22 87.63,51.44 84.45,48.26 81.28,48.26 81.28,52.7 83.82,55.24 R35.1
N$57  (via drill 0.61)
  Top 0.381: v157.48,66.04 v157.48,60.96 | v90.17,67.31 90.17,57.78 88.9,56.52 R36.1
  Bottom 0.381: v157.48,60.96 150.5,60.96 Q3.2 | v157.48,66.04 156.84,66.67 111.76,66.67 111.12,67.31 v90.17,67.31
N$58  (via drill 0.61)
  Top 0.381: v163.83,78.11 163.83,62.87 162.56,61.59 Q2.2 | v100.97,78.11 92.71,69.85 92.71,57.78 93.98,56.52 R37.1
  Bottom 0.381: v100.97,78.11 v163.83,78.11
N$59
  Top 0.381: R38.2 73.66,66.67 73.66,67.94 R28.2
  Bottom 0.381: E19.6 46.99,71.12 48.26,69.85 71.75,69.85 73.03,68.58 R28.2
N$60  (via drill 0.61)
  Top 0.381: E5.8 218.44,85.09 218.44,72.39 E5.3 217.81,70.48 203.84,56.52 v203.84,55.88 | E12.8 134.62,85.09 134.62,72.39 E12.3 134.62,69.85 134.62,61.59 Q4.1 134.62,60.33 134.62,58.42 v137.16,55.88
  Bottom 0.381: v203.84,55.88 v137.16,55.88
N$61  (via drill 0.61)
  Top 0.381: E4.8 231.14,85.09 231.14,72.39 E4.3 230.5,70.48 224.79,64.77 v224.79,57.15 | E11.8 147.32,85.09 147.32,72.39 E11.3 147.32,69.85 147.32,61.59 Q3.1 146.69,60.96 146.69,57.78 v147.32,57.15
  Bottom 0.381: v224.79,57.15 v147.32,57.15
N$62  (via drill 0.61)
  Top 0.381: E3.3 243.84,72.39 243.84,85.09 E3.8 | Q2.1 160.02,61.59 160.02,69.85 E9.3 160.02,72.39 v160.02,79.38 160.02,85.09 E9.8
  Bottom 0.381: v160.02,79.38 164.47,79.38 165.1,80.01 234.95,80.01 243.21,71.75 E3.3
N$63
  Top 0.381: D6.A 210.82,47.62 216.53,41.91 216.53,26.04 217.17,25.4 221.62,25.4 223.52,23.5 R40.2
N$64
  Top 0.381: D2.A 240.66,30.48 239.4,31.75 235.59,31.75 235.59,30.48 228.6,23.5 R41.2
N$65
  Top 0.381: D5.A 210.82,29.84 216.53,24.13 220.98,24.13 220.98,23.5 R42.2
N$66
  Top 0.381: D7.A 180.34,29.84 182.25,27.94 182.25,22.86 R43.2
N$67  (via drill 0.61)
  Top 0.381: v241.3,21.59 241.3,13.34 D1.A
  Bottom 0.381: v241.3,21.59 240.03,22.86 231.78,22.86 R44.2
N$68
  Top 0.381: D4.A 210.82,13.34 218.44,20.95 218.44,22.23 R45.2
N$69
  Top 0.381: D8.A 180.34,47.62 183.51,44.45 183.51,25.4 185.42,23.5 R46.2
N$70  (via drill 0.61)
  Top 0.381: v50.16,66.04 50.16,76.83 46.35,80.64 E19.2 | v177.8,59.69 177.8,48.9 D8.K
  Bottom 0.381: v50.16,66.04 52.7,63.5 109.86,63.5 111.12,62.23 118.75,62.23 121.28,59.69 v177.8,59.69
N$71  (via drill 0.61)
  Top 0.381: v100.33,5.08 100.33,6.99 99.06,8.26 99.06,43.18 103.5,47.62 E17.1 | v171.45,1.91 180.97,11.43 v205.74,11.43
  Bottom 0.381: v100.33,5.08 103.5,1.91 v171.45,1.91 | v205.74,11.43 206.38,12.06 208.28,12.06 D4.K
N$72  (via drill 0.61)
  Top 0.381: v100.33,24.13 100.33,41.91 103.5,45.09 E17.2 | v203.2,24.77 207.01,20.95 207.01,11.43 209.55,8.89 238.12,8.89 238.12,12.7 D1.K
  Bottom 0.381: v100.33,24.13 179.07,24.13 179.71,24.77 v203.2,24.77
N$73  (via drill 0.61)
  Top 0.381: v109.22,21.59 109.22,39.37 102.87,39.37 102.23,40.01 102.23,41.27 103.5,42.55 E17.3 | v171.45,20.32 177.8,26.67 177.8,29.84 D7.K
  Bottom 0.381: v109.22,21.59 156.84,21.59 158.12,20.32 v171.45,20.32
N$74  (via drill 0.61)
  Top 0.381: v109.86,49.53 109.86,46.35 104.78,41.27 E17.4 | v116.2,52.07 117.47,53.34 v117.47,64.77 | v203.84,64.77 202.56,63.5 202.56,41.91 208.28,36.2 208.28,31.11 D5.K
  Bottom 0.381: v109.86,49.53 112.39,52.07 v116.2,52.07 | v203.84,64.77 v117.47,64.77
N$75  (via drill 0.61)
  Top 0.381: v232.41,10.16 232.41,23.5 238.76,29.84 D2.K | v97.79,9.53 v97.79,41.27
  Bottom 0.381: v232.41,10.16 186.06,10.16 184.78,11.43 175.26,11.43 167,3.17 104.14,3.17 v97.79,9.53 | v97.79,41.27 100.97,38.1 102.87,38.1 E17.5
N$76
  Bottom 0.381: E17.6 105.41,35.56 107.95,38.1 108.58,38.1 109.86,39.37 179.07,39.37 186.69,46.99 206.38,46.99 207.65,48.26 D6.K
N$77  (via drill 0.61)
  Top 0.381: v238.76,40.64 238.76,47.62 D3.K
  Bottom 0.381: v238.76,40.64 229.87,31.75 221.62,31.75 219.07,29.21 116.2,29.21 113.67,31.75 106.68,31.75 105.41,33.02 E17.7
NUM
  Bottom 0.381: E20.10 36.83,15.24 101.6,15.24 103.5,13.34 114.94,13.34 116.2,14.61 J2.11
RUN  (via drill 0.61)
  Top 0.381: RUN.1 376.56,6.35 376.56,16.51 RUN.2 | R9.2 220.98,52.7 219.07,50.8 219.07,47.62 220.34,46.35 E2.2 220.34,45.09 219.07,43.81 219.07,29.21 224.79,23.5 v224.79,11.43
  Bottom 0.381: v224.79,11.43 279.4,11.43 283.21,7.62 374.01,7.62 375.29,6.35 RUN.1
SHLT\  (via drill 0.61)
  Top 0.381: SHLT\.1 353.69,6.35 353.69,16.51 SHLT\.2 | v140.97,25.4 140.97,10.16 142.24,8.89 J1.5 | v217.81,26.67 217.81,53.34 R19.2 218.44,53.98 218.44,54.61 221.62,54.61 222.25,53.98 222.25,49.53 221.62,48.9 E2.1
  Bottom 0.381: v140.97,25.4 142.24,26.67 212.72,26.67 | v217.81,26.67 212.72,26.67 | 212.72,26.67 219.07,20.32 351.15,20.32 352.43,19.05 SHLT\.2
STHIS\  (via drill 0.61)
  Top 0.381: v200.66,14.61 201.93,15.88 v201.93,35.56
  Bottom 0.381: v200.66,14.61 160.02,14.61 158.75,13.34 130.81,13.34 130.81,6.35 131.44,5.71 137.79,5.71 139.06,6.99 J1.4 | v201.93,35.56 219.71,35.56 E2.6
VCC  (via drill 0.61)
  Top 0.381: C3.1 194.31,27.3 194.31,14.61 193.04,13.34 R7.1 | R18.1 247.01,12.7 248.28,12.7 R17.1 249.56,12.7 250.82,12.7 R16.1 252.09,12.7 253.37,12.7 R15.1 254.63,12.7 255.91,12.7 R14.1 | 257.81,21.59 257.81,14.61 256.54,13.34 R14.1 | 257.81,21.59 257.81,27.3 C1.1 | R14.1 257.18,12.7 258.44,12.7 R13.1 259.71,12.7 260.99,12.7 R11.1 262.25,12.7 263.52,12.7 R12.1 | E8.3 174.62,75.56 174.62,74.3 E8.4 174.62,73.03 174.62,71.75 E8.5 175.9,70.48 176.53,69.85 | 176.53,69.85 177.16,69.22 177.16,66.04 181.61,61.59 C4.1 | 176.53,69.85 184.15,69.85 184.78,70.48 184.78,79.38 183.51,80.64 E8.16 | 232.41,56.52 232.41,61.59 231.14,62.87 R21.1 230.5,63.5 229.24,63.5 R20.1 | 232.41,56.52 232.41,30.48 227.97,30.48 C2.1 | 232.41,56.52 229.87,53.98 229.87,49.53 229.24,48.9 E2.14 | 257.81,21.59 266.06,21.59 266.06,46.35 264.16,48.26 260.35,48.26 E1.16 | E21.14 34.92,53.98 34.29,54.61 34.29,62.87 C13.1 | E18.16 52.7,53.98 52.7,55.88 48.26,60.33 R2.1 48.26,61.59 52.07,65.41 C10.1 51.44,66.04 51.44,81.92 52.7,83.19 E19.14 | 15.88,13.34 15.88,8.89 16.51,8.26 C14.1 | 15.88,13.34 17.14,14.61 E23.10 | 15.88,13.34 11.43,17.78 E23.4 | C12.1 34.29,34.92 34.92,34.29 34.92,26.04 E20.14 | E24.8 17.14,37.47 16.51,36.83 16.51,36.2 C15.1 16.51,34.92 16.51,26.67 17.14,26.04 E23.14 17.14,24.77 15.88,23.5 15.88,22.23 17.14,20.95 E23.12 | E24.5 9.53,43.81 9.53,45.09 E24.4 9.53,46.35 9.53,47.62 E24.3 9.53,48.9 9.53,50.16 E24.2 | E24.14 17.14,53.98 17.14,64.77 16.51,65.41 C16.1 16.51,66.67 16.51,67.31 10.79,73.03 E25.5 | C6.1 146.05,28.57 144.78,29.84 144.78,34.29 140.97,38.1 E13.5 139.06,38.73 139.06,40.01 E13.4 139.06,41.27 139.06,42.55 E13.3
  Top 0.381: C5.1 163.83,31.11 163.19,31.75 163.19,46.35 164.47,47.62 E10.14 | E16.5 121.28,38.73 121.28,40.01 E16.4 121.28,41.27 121.28,42.55 E16.3 | v116.84,38.1 116.84,31.11 R4.1 116.84,29.84 v114.94,27.94 115.57,27.3 v115.57,17.14 | C7.1 128.27,27.3 131.44,24.13 131.44,15.88 J1.16 | C20.+ 85.09,51.44 85.09,76.83 86.36,78.11 R31.1 | R43.1 183.51,12.7 184.78,12.7 R46.1 186.06,12.7 187.32,12.7 R3.1 188.59,12.7 189.87,12.7 R5.1 191.13,12.7 192.41,12.7 R7.1 | R8.1 197.49,12.7 196.22,12.7 R6.1 194.94,12.7 193.68,12.7 R7.1 | R41.1 229.24,12.7 230.5,12.7 R44.1 | R45.1 219.07,12.7 220.34,12.7 R42.1 221.62,12.7 222.88,12.7 R40.1 | R19.1 219.07,63.5 220.34,63.5 R9.1 221.62,63.5 222.88,63.5 R22.1 | R28.1 74.3,78.74 75.56,78.74 R33.1 76.83,78.74 78.11,78.74 R27.1 79.38,78.74 80.64,78.74 R32.1 81.92,78.74 83.19,78.74 R26.1 84.45,78.74 85.72,78.74 R31.1 | R24.1 94.61,78.74 95.89,78.74 R29.1 | R31.1 87,78.74 88.27,78.74 R25.1 89.53,78.74 90.81,78.74 R30.1
  Bottom 0.381: R18.1 245.75,12.7 244.47,13.97 233.04,13.97 231.78,12.7 R44.1 | E1.16 257.81,48.26 256.54,49.53 231.14,49.53 229.87,48.26 E2.14 227.33,48.26 226.06,49.53 193.04,49.53 | C4.1 182.25,60.96 199.39,60.96 201.93,63.5 217.81,63.5 R19.1 | E22.16 36.83,83.82 38.1,85.09 50.8,85.09 52.07,83.82 E19.14 | E18.3 46.99,48.26 52.07,53.34 E18.16 54.61,53.34 56.52,51.44 82.55,51.44 C20.+ 85.09,50.16 87,50.16 | C13.1 34.92,63.5 37.47,60.96 47.62,60.96 R2.1 | E23.4 11.43,17.78 13.97,20.32 16.51,20.32 E23.12 | C11.1 33.66,7.62 32.38,8.89 18.41,8.89 17.14,7.62 C14.1 | E20.14 36.83,25.4 40.01,25.4 R1.2 41.27,25.4 43.81,25.4 51.44,33.02 C9.1 | E24.2 11.43,50.8 13.97,50.8 16.51,53.34 E24.14 19.05,53.34 20.32,54.61 33.02,54.61 34.29,53.34 E21.14 | E24.8 16.51,38.1 11.43,43.18 E24.5 | C12.1 33.66,35.56 32.38,34.29 18.41,34.29 17.14,35.56 C15.1 | 193.04,49.53 194.31,48.26 E6.16 | 193.04,49.53 167.64,49.53 | 167.64,49.53 166.37,48.26 E10.14 | 167.64,49.53 149.86,49.53 148.59,48.26 E13.16 146.05,48.26 140.97,43.18 E13.3 138.43,43.18 137.16,44.45 134.62,44.45 130.81,48.26 E16.16 128.27,48.26 124.46,48.26 123.19,46.99 114.3,46.99 113.03,48.26 E17.16 110.49,48.26 106.68,48.26 104.78,50.16 95.25,50.16 C19.+ 92.71,50.16 87,50.16 | v114.94,27.94 111.12,27.94 C8.1 | v116.84,38.1 120.65,38.1 E16.5 | J2.16 104.78,15.88 106.05,17.14 v115.57,17.14 130.18,17.14 131.44,15.88 J1.16 | 87,50.16 102.87,34.29 105.41,34.29 106.05,33.66 107.31,33.66 107.95,34.29 113.67,34.29 116.84,31.11 R4.1 | R10.1 160.66,12.7 182.25,12.7 R43.1 | R8.1 198.75,12.7 199.39,13.34 207.01,13.34 207.65,13.97 216.53,13.97 217.81,12.7 R45.1
  Bottom 0.381: R40.1 224.16,12.7 225.43,12.7 R39.1 226.69,12.7 227.97,12.7 R41.1 | R22.1 224.16,63.5 225.43,63.5 R23.1 226.69,63.5 227.97,63.5 R20.1 | R30.1 92.08,78.74 93.34,78.74 R24.1 | VCC.1 8.89,29.21 12.7,25.4 16.51,25.4 E23.14

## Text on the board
Top: VRS/CEM | PDP-8/A Console, Board 1
Bottom: VRS/CEM | PDP-8/A Console, Board 1
tValues: VRS/CEM | PDP-8/A Console, Board 1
